VERSION 5.7 ;
  NOWIREEXTENSIONATPIN ON ;
  DIVIDERCHAR "/" ;
  BUSBITCHARS "[]" ;
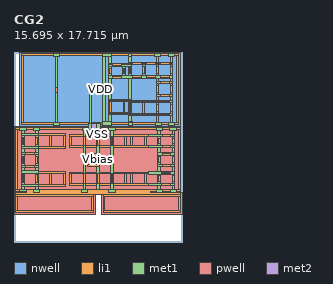
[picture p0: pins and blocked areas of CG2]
MACRO CG2
  CLASS BLOCK ;
  FOREIGN CG2 ;
  ORIGIN -1.560 1.405 ;
  SIZE 15.695 BY 17.715 ;
  PIN VDD
    ANTENNAGATEAREA 5.130000 ;
    ANTENNADIFFAREA 9.903700 ;
    PORT
      LAYER nwell ;
        RECT 2.115 9.355 17.075 16.310 ;
      LAYER li1 ;
        RECT 2.295 15.960 16.895 16.130 ;
        RECT 2.295 9.705 2.465 15.960 ;
        RECT 10.745 15.025 11.585 15.195 ;
        RECT 12.595 15.150 13.435 15.320 ;
        RECT 13.885 15.150 14.725 15.320 ;
        RECT 15.175 15.150 16.015 15.320 ;
        RECT 10.435 14.270 10.605 14.810 ;
        RECT 11.725 14.270 11.895 14.810 ;
        RECT 12.285 14.305 12.455 14.935 ;
        RECT 13.575 14.305 13.745 14.935 ;
        RECT 14.865 14.305 15.035 14.935 ;
        RECT 16.155 14.305 16.325 14.935 ;
        RECT 10.745 13.885 11.585 14.055 ;
        RECT 12.595 13.920 13.435 14.090 ;
        RECT 13.885 13.920 14.725 14.090 ;
        RECT 15.175 13.920 16.015 14.090 ;
        RECT 15.175 13.380 16.015 13.550 ;
        RECT 5.445 12.495 5.615 13.035 ;
        RECT 9.875 12.410 10.045 13.250 ;
        RECT 10.435 12.590 10.605 13.130 ;
        RECT 14.865 12.535 15.035 13.165 ;
        RECT 16.155 12.535 16.325 13.165 ;
        RECT 15.175 12.150 16.015 12.320 ;
        RECT 10.435 11.780 12.460 11.835 ;
        RECT 10.435 11.665 16.015 11.780 ;
        RECT 10.435 10.695 10.605 11.665 ;
        RECT 11.725 10.695 11.895 11.665 ;
        RECT 12.285 11.610 16.015 11.665 ;
        RECT 12.285 10.695 12.455 11.610 ;
        RECT 10.435 10.550 12.455 10.695 ;
        RECT 13.575 10.550 13.745 11.610 ;
        RECT 14.865 10.765 15.035 11.395 ;
        RECT 16.155 10.765 16.325 11.395 ;
        RECT 10.435 10.525 16.015 10.550 ;
        RECT 12.285 10.380 16.015 10.525 ;
        RECT 12.335 9.705 12.530 9.710 ;
        RECT 16.725 9.705 16.895 15.960 ;
        RECT 2.295 9.535 16.895 9.705 ;
      LAYER met1 ;
        RECT 5.235 15.900 5.825 16.190 ;
        RECT 5.415 9.770 5.645 15.900 ;
        RECT 9.845 15.895 10.635 16.175 ;
        RECT 12.195 15.910 12.545 16.190 ;
        RECT 9.845 9.785 10.075 15.895 ;
        RECT 10.405 15.225 10.635 15.895 ;
        RECT 12.255 15.350 12.485 15.910 ;
        RECT 14.655 15.900 15.245 16.190 ;
        RECT 15.965 15.900 16.555 16.190 ;
        RECT 14.835 15.350 15.065 15.900 ;
        RECT 16.125 15.350 16.355 15.900 ;
        RECT 12.255 15.225 16.355 15.350 ;
        RECT 10.405 15.120 16.355 15.225 ;
        RECT 10.405 14.995 12.485 15.120 ;
        RECT 10.405 14.120 10.635 14.995 ;
        RECT 11.695 14.120 11.925 14.995 ;
        RECT 12.255 14.120 12.485 14.995 ;
        RECT 13.545 14.120 13.775 15.120 ;
        RECT 14.835 14.120 15.065 15.120 ;
        RECT 16.125 14.120 16.355 15.120 ;
        RECT 10.405 13.855 16.355 14.120 ;
        RECT 10.405 9.785 10.635 13.855 ;
        RECT 5.235 9.480 5.825 9.770 ;
        RECT 9.845 9.495 10.635 9.785 ;
        RECT 12.255 9.830 12.485 13.855 ;
        RECT 14.835 13.580 15.065 13.855 ;
        RECT 16.125 13.580 16.355 13.855 ;
        RECT 14.835 13.345 16.355 13.580 ;
        RECT 14.835 12.355 15.065 13.345 ;
        RECT 16.125 12.355 16.355 13.345 ;
        RECT 14.835 12.120 16.355 12.355 ;
        RECT 14.835 11.815 15.065 12.120 ;
        RECT 16.125 11.815 16.355 12.120 ;
        RECT 14.835 11.580 16.355 11.815 ;
        RECT 14.835 10.580 15.065 11.580 ;
        RECT 16.125 10.580 16.355 11.580 ;
        RECT 14.835 10.345 16.355 10.580 ;
        RECT 12.255 9.480 12.590 9.830 ;
        RECT 14.835 9.765 15.065 10.345 ;
        RECT 16.125 9.765 16.355 10.345 ;
        RECT 14.730 9.475 15.320 9.765 ;
        RECT 15.960 9.475 16.550 9.765 ;
    END
  END VDD
  PIN VSS
    ANTENNAGATEAREA 12.190000 ;
    ANTENNADIFFAREA 18.044500 ;
    PORT
      LAYER pwell ;
        RECT 1.600 3.260 17.080 9.355 ;
        RECT 1.600 3.190 2.740 3.260 ;
        RECT 1.560 1.180 9.130 3.190 ;
        RECT 14.290 3.165 17.080 3.260 ;
        RECT 9.685 1.155 17.255 3.165 ;
      LAYER li1 ;
        RECT 1.740 9.055 17.075 9.225 ;
        RECT 1.740 3.455 1.910 9.055 ;
        RECT 2.655 8.540 6.355 8.710 ;
        RECT 2.315 7.660 2.485 8.370 ;
        RECT 3.605 7.660 3.775 8.370 ;
        RECT 4.895 7.490 5.065 8.540 ;
        RECT 6.185 7.490 6.355 8.540 ;
        RECT 2.655 7.320 6.355 7.490 ;
        RECT 6.745 8.460 14.875 8.630 ;
        RECT 15.385 8.460 16.165 8.630 ;
        RECT 6.745 7.580 6.915 8.460 ;
        RECT 8.035 7.580 8.205 8.460 ;
        RECT 9.325 7.580 9.495 8.460 ;
        RECT 10.615 7.580 10.785 8.460 ;
        RECT 11.905 7.580 12.075 8.460 ;
        RECT 12.465 7.580 12.635 8.460 ;
        RECT 13.755 7.580 13.925 8.460 ;
        RECT 15.045 7.750 15.215 8.290 ;
        RECT 16.335 7.750 16.505 8.290 ;
        RECT 6.745 7.410 14.875 7.580 ;
        RECT 15.385 7.410 16.165 7.580 ;
        RECT 2.655 6.780 3.435 6.950 ;
        RECT 15.385 6.700 16.165 6.870 ;
        RECT 2.315 5.900 2.485 6.610 ;
        RECT 3.605 5.900 3.775 6.610 ;
        RECT 8.035 5.990 8.205 6.530 ;
        RECT 10.615 5.990 10.785 6.530 ;
        RECT 15.045 5.990 15.215 6.530 ;
        RECT 16.335 5.990 16.505 6.530 ;
        RECT 2.655 5.560 3.435 5.730 ;
        RECT 15.385 5.650 16.165 5.820 ;
        RECT 2.655 5.020 6.355 5.190 ;
        RECT 2.315 4.140 2.485 4.850 ;
        RECT 3.605 4.140 3.775 4.850 ;
        RECT 4.895 3.970 5.065 5.020 ;
        RECT 6.185 3.970 6.355 5.020 ;
        RECT 2.655 3.800 6.355 3.970 ;
        RECT 6.745 4.940 14.875 5.110 ;
        RECT 15.355 4.940 16.195 5.110 ;
        RECT 6.745 4.060 6.915 4.940 ;
        RECT 8.035 4.060 8.205 4.940 ;
        RECT 9.325 4.060 9.495 4.940 ;
        RECT 10.615 4.060 10.785 4.940 ;
        RECT 11.905 4.060 12.075 4.940 ;
        RECT 12.465 4.060 12.635 4.940 ;
        RECT 13.755 4.060 13.925 4.940 ;
        RECT 15.045 4.230 15.215 4.770 ;
        RECT 16.335 4.230 16.505 4.770 ;
        RECT 6.745 3.890 14.875 4.060 ;
        RECT 15.355 3.890 16.195 4.060 ;
        RECT 16.905 3.455 17.075 9.055 ;
        RECT 1.740 2.985 17.075 3.455 ;
        RECT 1.740 2.840 8.950 2.985 ;
        RECT 1.740 1.530 1.910 2.840 ;
        RECT 8.780 1.530 8.950 2.840 ;
        RECT 1.740 1.360 8.950 1.530 ;
        RECT 9.865 2.815 17.075 2.985 ;
        RECT 9.865 1.505 10.035 2.815 ;
        RECT 16.905 1.505 17.075 2.815 ;
        RECT 9.865 1.335 17.075 1.505 ;
      LAYER met1 ;
        RECT 2.080 8.990 2.700 9.280 ;
        RECT 3.345 9.275 3.965 9.285 ;
        RECT 3.335 9.005 3.965 9.275 ;
        RECT 7.945 9.025 8.295 9.285 ;
        RECT 3.345 8.995 3.965 9.005 ;
        RECT 2.285 8.740 2.515 8.990 ;
        RECT 3.575 8.740 3.815 8.995 ;
        RECT 2.285 8.510 3.815 8.740 ;
        RECT 2.285 7.520 2.515 8.510 ;
        RECT 3.575 7.520 3.815 8.510 ;
        RECT 2.285 7.290 3.815 7.520 ;
        RECT 2.285 6.980 2.515 7.290 ;
        RECT 3.575 6.980 3.815 7.290 ;
        RECT 2.285 6.750 3.815 6.980 ;
        RECT 2.285 5.760 2.515 6.750 ;
        RECT 3.575 5.770 3.815 6.750 ;
        RECT 3.575 5.760 3.805 5.770 ;
        RECT 2.285 5.530 3.805 5.760 ;
        RECT 2.285 5.220 2.515 5.530 ;
        RECT 3.575 5.220 3.805 5.530 ;
        RECT 2.285 4.990 3.805 5.220 ;
        RECT 2.285 4.000 2.515 4.990 ;
        RECT 3.575 4.000 3.805 4.990 ;
        RECT 2.285 3.770 3.805 4.000 ;
        RECT 2.285 3.510 2.515 3.770 ;
        RECT 3.575 3.515 3.805 3.770 ;
        RECT 2.110 3.220 2.730 3.510 ;
        RECT 3.385 3.250 3.975 3.515 ;
        RECT 8.005 3.505 8.235 9.025 ;
        RECT 10.390 9.000 11.010 9.290 ;
        RECT 10.585 3.505 10.815 9.000 ;
        RECT 14.820 8.995 15.440 9.285 ;
        RECT 16.100 9.010 16.720 9.300 ;
        RECT 14.985 8.660 15.245 8.995 ;
        RECT 16.305 8.660 16.535 9.010 ;
        RECT 14.110 8.430 16.535 8.660 ;
        RECT 14.985 7.610 15.245 8.430 ;
        RECT 16.305 7.610 16.535 8.430 ;
        RECT 14.110 7.380 16.535 7.610 ;
        RECT 14.985 6.900 15.245 7.380 ;
        RECT 16.305 6.900 16.535 7.380 ;
        RECT 14.985 6.670 16.535 6.900 ;
        RECT 14.985 5.850 15.245 6.670 ;
        RECT 16.305 5.850 16.535 6.670 ;
        RECT 14.985 5.620 16.535 5.850 ;
        RECT 14.985 5.140 15.245 5.620 ;
        RECT 16.305 5.140 16.535 5.620 ;
        RECT 14.110 4.910 16.535 5.140 ;
        RECT 14.985 4.090 15.245 4.910 ;
        RECT 16.305 4.090 16.535 4.910 ;
        RECT 14.110 3.860 16.535 4.090 ;
        RECT 14.985 3.515 15.245 3.860 ;
        RECT 16.305 3.525 16.535 3.860 ;
        RECT 7.815 3.255 8.405 3.505 ;
        RECT 10.405 3.250 10.995 3.505 ;
        RECT 14.815 3.225 15.405 3.515 ;
        RECT 16.105 3.235 16.725 3.525 ;
    END
  END VSS
  PIN Vbias
    ANTENNAGATEAREA 0.500000 ;
    ANTENNADIFFAREA 0.377000 ;
    PORT
      LAYER li1 ;
        RECT 8.585 12.410 8.755 13.250 ;
        RECT 8.375 6.700 9.495 6.870 ;
        RECT 9.325 5.820 9.495 6.700 ;
        RECT 8.375 5.650 9.495 5.820 ;
      LAYER met1 ;
        RECT 8.555 9.680 8.785 13.230 ;
        RECT 8.500 9.040 8.820 9.680 ;
        RECT 9.260 9.040 9.580 9.680 ;
        RECT 9.295 3.455 9.525 9.040 ;
      LAYER met2 ;
        RECT 8.500 9.040 9.580 9.680 ;
    END
  END Vbias
  OBS
      LAYER li1 ;
        RECT 8.585 15.445 10.045 15.615 ;
        RECT 8.585 15.100 8.755 15.445 ;
        RECT 3.175 14.930 8.755 15.100 ;
        RECT 2.865 14.175 3.035 14.715 ;
        RECT 4.155 14.175 4.325 14.715 ;
        RECT 5.445 13.960 5.615 14.930 ;
        RECT 6.735 13.960 6.905 14.930 ;
        RECT 8.025 13.995 8.195 14.930 ;
        RECT 8.585 14.175 8.755 14.930 ;
        RECT 9.875 14.175 10.045 15.445 ;
        RECT 8.585 14.005 10.045 14.175 ;
        RECT 8.585 13.995 8.755 14.005 ;
        RECT 7.685 13.960 8.755 13.995 ;
        RECT 3.175 13.825 8.755 13.960 ;
        RECT 3.175 13.790 7.855 13.825 ;
        RECT 8.925 13.465 9.705 13.635 ;
        RECT 12.285 13.515 13.745 13.550 ;
        RECT 3.175 13.250 4.015 13.420 ;
        RECT 4.495 13.250 5.275 13.420 ;
        RECT 5.785 13.250 6.565 13.420 ;
        RECT 6.735 13.250 8.195 13.420 ;
        RECT 10.775 13.380 13.745 13.515 ;
        RECT 13.915 13.380 14.695 13.550 ;
        RECT 10.775 13.345 12.455 13.380 ;
        RECT 2.865 12.495 3.035 13.035 ;
        RECT 4.155 12.495 4.325 13.035 ;
        RECT 6.735 12.280 6.905 13.250 ;
        RECT 8.025 12.280 8.195 13.250 ;
        RECT 11.725 12.590 11.895 13.130 ;
        RECT 12.285 12.375 12.455 13.345 ;
        RECT 3.175 12.110 4.015 12.280 ;
        RECT 4.495 12.110 5.275 12.280 ;
        RECT 5.785 12.110 6.565 12.280 ;
        RECT 6.735 12.110 8.195 12.280 ;
        RECT 10.775 12.320 12.455 12.375 ;
        RECT 13.575 12.320 13.745 13.380 ;
        RECT 10.775 12.205 13.745 12.320 ;
        RECT 8.925 12.025 9.705 12.195 ;
        RECT 12.285 12.150 13.745 12.205 ;
        RECT 13.915 12.150 14.695 12.320 ;
        RECT 3.175 11.655 8.195 11.740 ;
        RECT 3.175 11.570 10.045 11.655 ;
        RECT 2.865 10.815 3.035 11.355 ;
        RECT 4.155 10.815 4.325 11.355 ;
        RECT 5.445 10.600 5.615 11.570 ;
        RECT 6.735 10.600 6.905 11.570 ;
        RECT 8.025 11.485 10.045 11.570 ;
        RECT 8.025 10.600 8.195 11.485 ;
        RECT 8.585 10.600 8.755 11.485 ;
        RECT 3.175 10.430 8.755 10.600 ;
        RECT 8.585 10.215 8.755 10.430 ;
        RECT 9.875 10.215 10.045 11.485 ;
        RECT 8.585 10.045 10.045 10.215 ;
        RECT 3.945 6.780 4.725 6.950 ;
        RECT 5.205 6.780 6.045 6.950 ;
        RECT 7.085 6.700 7.865 6.870 ;
        RECT 9.665 6.700 10.445 6.870 ;
        RECT 10.955 6.700 11.735 6.870 ;
        RECT 12.465 6.700 13.925 6.870 ;
        RECT 14.095 6.700 14.875 6.870 ;
        RECT 4.895 5.900 5.065 6.610 ;
        RECT 6.185 5.900 6.355 6.610 ;
        RECT 6.745 5.990 6.915 6.530 ;
        RECT 11.905 5.990 12.075 6.530 ;
        RECT 12.465 5.820 12.635 6.700 ;
        RECT 13.755 5.820 13.925 6.700 ;
        RECT 3.945 5.560 4.725 5.730 ;
        RECT 5.205 5.560 6.045 5.730 ;
        RECT 7.085 5.650 7.865 5.820 ;
        RECT 9.665 5.650 10.445 5.820 ;
        RECT 10.955 5.650 11.735 5.820 ;
        RECT 12.465 5.650 13.925 5.820 ;
        RECT 14.095 5.650 14.875 5.820 ;
        RECT 2.390 2.010 4.550 2.360 ;
        RECT 6.140 2.010 8.300 2.360 ;
        RECT 10.515 1.985 12.675 2.335 ;
        RECT 14.265 1.985 16.425 2.335 ;
      LAYER met1 ;
        RECT 2.835 14.900 4.355 15.130 ;
        RECT 2.835 13.990 3.065 14.900 ;
        RECT 4.125 13.990 4.355 14.900 ;
        RECT 2.835 13.760 4.355 13.990 ;
        RECT 2.835 13.450 3.065 13.760 ;
        RECT 4.125 13.450 4.355 13.760 ;
        RECT 2.835 13.220 4.355 13.450 ;
        RECT 4.510 13.220 5.260 13.685 ;
        RECT 5.800 13.220 6.945 13.685 ;
        RECT 9.005 13.665 9.645 13.685 ;
        RECT 8.940 13.435 9.690 13.665 ;
        RECT 9.005 13.365 9.645 13.435 ;
        RECT 13.935 13.350 14.675 13.580 ;
        RECT 2.835 12.310 3.065 13.220 ;
        RECT 4.125 12.310 4.355 13.220 ;
        RECT 6.705 12.310 6.945 13.220 ;
        RECT 11.695 12.610 12.105 13.110 ;
        RECT 12.840 12.980 13.775 13.145 ;
        RECT 2.835 12.080 4.355 12.310 ;
        RECT 2.835 11.770 3.065 12.080 ;
        RECT 4.125 11.770 4.355 12.080 ;
        RECT 4.510 11.945 5.260 12.310 ;
        RECT 5.800 11.945 6.945 12.310 ;
        RECT 8.940 11.945 9.690 12.265 ;
        RECT 2.835 11.540 4.355 11.770 ;
        RECT 2.835 10.630 3.065 11.540 ;
        RECT 4.125 10.630 4.355 11.540 ;
        RECT 2.835 10.400 4.355 10.630 ;
        RECT 4.125 7.990 4.355 10.400 ;
        RECT 3.960 7.210 4.715 7.990 ;
        RECT 3.960 6.750 4.710 7.070 ;
        RECT 3.960 5.760 4.205 6.750 ;
        RECT 4.455 5.760 4.710 6.750 ;
        RECT 3.960 5.440 4.710 5.760 ;
        RECT 4.860 7.040 5.180 9.010 ;
        RECT 6.155 7.040 6.385 8.960 ;
        RECT 4.860 6.720 6.385 7.040 ;
        RECT 4.860 5.790 5.180 6.720 ;
        RECT 6.155 5.790 6.385 6.720 ;
        RECT 4.860 5.470 6.385 5.790 ;
        RECT 3.960 4.520 4.710 5.300 ;
        RECT 4.200 2.310 4.520 4.520 ;
        RECT 4.860 3.450 5.180 5.470 ;
        RECT 4.860 3.280 5.110 3.450 ;
        RECT 6.155 3.280 6.385 5.470 ;
        RECT 6.705 3.455 6.945 11.945 ;
        RECT 7.150 6.900 7.790 7.020 ;
        RECT 11.875 6.970 12.105 12.610 ;
        RECT 9.735 6.900 10.375 6.970 ;
        RECT 11.020 6.900 12.105 6.970 ;
        RECT 7.100 6.670 7.850 6.900 ;
        RECT 9.680 6.670 10.430 6.900 ;
        RECT 10.970 6.670 12.105 6.900 ;
        RECT 9.735 6.650 10.375 6.670 ;
        RECT 11.020 6.650 12.105 6.670 ;
        RECT 11.875 5.890 12.105 6.650 ;
        RECT 9.730 5.850 10.370 5.890 ;
        RECT 11.025 5.850 12.105 5.890 ;
        RECT 7.100 5.620 7.850 5.850 ;
        RECT 9.680 5.620 10.430 5.850 ;
        RECT 10.970 5.620 12.105 5.850 ;
        RECT 7.165 5.500 7.805 5.620 ;
        RECT 9.730 5.570 10.370 5.620 ;
        RECT 11.025 5.570 12.105 5.620 ;
        RECT 11.875 3.455 12.105 5.570 ;
        RECT 12.835 12.555 13.775 12.980 ;
        RECT 12.835 10.785 13.475 12.555 ;
        RECT 14.185 12.350 14.415 13.350 ;
        RECT 13.935 11.570 14.675 12.350 ;
        RECT 12.835 3.285 13.050 10.785 ;
        RECT 13.240 3.285 13.475 10.785 ;
        RECT 13.935 10.650 14.675 11.430 ;
        RECT 14.185 9.720 14.415 10.650 ;
        RECT 13.670 9.080 13.990 9.720 ;
        RECT 14.135 9.080 14.455 9.720 ;
        RECT 13.725 6.010 13.955 9.080 ;
        RECT 14.170 6.650 14.810 6.970 ;
        RECT 4.860 2.960 5.180 3.280 ;
        RECT 6.110 2.960 6.430 3.280 ;
        RECT 12.835 2.965 13.475 3.285 ;
        RECT 13.695 3.285 13.955 6.010 ;
        RECT 14.165 5.570 14.805 5.890 ;
        RECT 13.695 2.965 14.015 3.285 ;
        RECT 6.165 2.310 6.485 2.350 ;
        RECT 2.420 2.060 4.525 2.310 ;
        RECT 6.165 2.060 8.270 2.310 ;
        RECT 12.330 2.285 12.650 2.470 ;
        RECT 6.165 2.030 6.485 2.060 ;
        RECT 10.545 2.035 12.650 2.285 ;
        RECT 14.290 2.285 14.610 2.470 ;
        RECT 14.290 2.035 16.395 2.285 ;
      LAYER met2 ;
        RECT 4.550 13.365 9.645 13.685 ;
        RECT 4.510 11.945 9.645 12.265 ;
        RECT 13.935 10.650 14.675 12.350 ;
        RECT 13.670 9.080 14.455 9.720 ;
        RECT 3.960 7.210 4.715 7.990 ;
        RECT 3.960 6.750 4.710 7.210 ;
        RECT 5.305 7.020 7.775 7.040 ;
        RECT 5.305 6.720 7.790 7.020 ;
        RECT 7.150 6.700 7.790 6.720 ;
        RECT 9.735 6.650 14.810 6.970 ;
        RECT 7.165 5.790 7.805 5.820 ;
        RECT 3.960 4.520 4.710 5.760 ;
        RECT 5.305 5.470 7.805 5.790 ;
        RECT 9.730 5.570 14.805 5.890 ;
        RECT 4.860 2.960 6.485 3.280 ;
        RECT 6.165 2.030 6.485 2.960 ;
        RECT 12.330 2.965 13.475 3.285 ;
        RECT 13.695 2.965 14.610 3.285 ;
        RECT 12.330 2.150 12.650 2.965 ;
        RECT 14.290 2.150 14.610 2.965 ;
  END
END CG2
END LIBRARY

